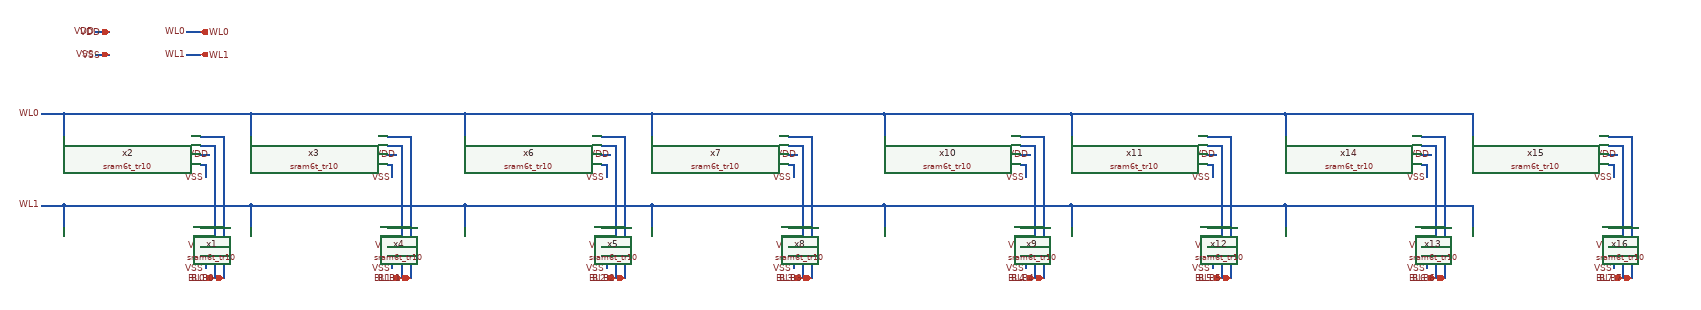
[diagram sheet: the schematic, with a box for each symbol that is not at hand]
v {xschem version=3.4.8RC file_version=1.3}
G {}
K {}
V {}
S {}
F {}
E {}
N 50 -560 50 -510 {lab=WL0}
N 50 -560 460 -560 {lab=WL0}
N 460 -560 460 -510 {lab=WL0}
N 0 -560 50 -560 {lab=WL0}
N 50 -360 50 -310 {lab=WL1}
N 50 -360 460 -360 {lab=WL1}
N 460 -360 460 -310 {lab=WL1}
N -0 -360 50 -360 {lab=WL1}
N 350 -490 380 -490 {lab=BL0}
N 380 -490 380 -200 {lab=BL0}
N 350 -290 380 -290 {lab=BL0}
N 350 -510 400 -510 {lab=BLB0}
N 400 -510 400 -200 {lab=BLB0}
N 350 -310 400 -310 {lab=BLB0}
N 760 -490 790 -490 {lab=BL1}
N 790 -490 790 -200 {lab=BL1}
N 760 -290 790 -290 {lab=BL1}
N 760 -510 810 -510 {lab=BLB1}
N 810 -510 810 -200 {lab=BLB1}
N 760 -310 810 -310 {lab=BLB1}
N 350 -270 370 -270 {lab=VDD}
N 350 -470 370 -470 {lab=VDD}
N 350 -450 360 -450 {lab=VSS}
N 360 -450 360 -420 {lab=VSS}
N 350 -250 360 -250 {lab=VSS}
N 360 -250 360 -220 {lab=VSS}
N 760 -450 770 -450 {lab=VSS}
N 770 -450 770 -420 {lab=VSS}
N 760 -250 770 -250 {lab=VSS}
N 770 -250 770 -220 {lab=VSS}
N 760 -470 780 -470 {lab=VDD}
N 760 -270 780 -270 {lab=VDD}
N 120 -740 150 -740 {lab=VDD}
N 120 -690 150 -690 {lab=VSS}
N 320 -740 350 -740 {lab=WL0}
N 320 -690 350 -690 {lab=WL1}
N 930 -560 930 -510 {lab=WL0}
N 930 -560 1340 -560 {lab=WL0}
N 1340 -560 1340 -510 {lab=WL0}
N 880 -560 930 -560 {lab=WL0}
N 930 -360 930 -310 {lab=WL1}
N 930 -360 1340 -360 {lab=WL1}
N 1340 -360 1340 -310 {lab=WL1}
N 880 -360 930 -360 {lab=WL1}
N 1230 -490 1260 -490 {lab=BL2}
N 1260 -490 1260 -200 {lab=BL2}
N 1230 -290 1260 -290 {lab=BL2}
N 1230 -510 1280 -510 {lab=BLB2}
N 1280 -510 1280 -200 {lab=BLB2}
N 1230 -310 1280 -310 {lab=BLB2}
N 1640 -490 1670 -490 {lab=BL3}
N 1670 -490 1670 -200 {lab=BL3}
N 1640 -290 1670 -290 {lab=BL3}
N 1640 -510 1690 -510 {lab=BLB3}
N 1690 -510 1690 -200 {lab=BLB3}
N 1640 -310 1690 -310 {lab=BLB3}
N 1230 -270 1250 -270 {lab=VDD}
N 1230 -470 1250 -470 {lab=VDD}
N 1230 -450 1240 -450 {lab=VSS}
N 1240 -450 1240 -420 {lab=VSS}
N 1230 -250 1240 -250 {lab=VSS}
N 1240 -250 1240 -220 {lab=VSS}
N 1640 -450 1650 -450 {lab=VSS}
N 1650 -450 1650 -420 {lab=VSS}
N 1640 -250 1650 -250 {lab=VSS}
N 1650 -250 1650 -220 {lab=VSS}
N 1640 -470 1660 -470 {lab=VDD}
N 1640 -270 1660 -270 {lab=VDD}
N 460 -560 880 -560 {lab=WL0}
N 460 -360 880 -360 {lab=WL1}
N 1850 -560 1850 -510 {lab=WL0}
N 1850 -560 2260 -560 {lab=WL0}
N 2260 -560 2260 -510 {lab=WL0}
N 1800 -560 1850 -560 {lab=WL0}
N 1850 -360 1850 -310 {lab=WL1}
N 1850 -360 2260 -360 {lab=WL1}
N 2260 -360 2260 -310 {lab=WL1}
N 1800 -360 1850 -360 {lab=WL1}
N 2150 -490 2180 -490 {lab=BL4}
N 2180 -490 2180 -200 {lab=BL4}
N 2150 -290 2180 -290 {lab=BL4}
N 2150 -510 2200 -510 {lab=BLB4}
N 2200 -510 2200 -200 {lab=BLB4}
N 2150 -310 2200 -310 {lab=BLB4}
N 2560 -490 2590 -490 {lab=BL5}
N 2590 -490 2590 -200 {lab=BL5}
N 2560 -290 2590 -290 {lab=BL5}
N 2560 -510 2610 -510 {lab=BLB5}
N 2610 -510 2610 -200 {lab=BLB5}
N 2560 -310 2610 -310 {lab=BLB5}
N 2150 -270 2170 -270 {lab=VDD}
N 2150 -470 2170 -470 {lab=VDD}
N 2150 -450 2160 -450 {lab=VSS}
N 2160 -450 2160 -420 {lab=VSS}
N 2150 -250 2160 -250 {lab=VSS}
N 2160 -250 2160 -220 {lab=VSS}
N 2560 -450 2570 -450 {lab=VSS}
N 2570 -450 2570 -420 {lab=VSS}
N 2560 -250 2570 -250 {lab=VSS}
N 2570 -250 2570 -220 {lab=VSS}
N 2560 -470 2580 -470 {lab=VDD}
N 2560 -270 2580 -270 {lab=VDD}
N 2730 -560 2730 -510 {lab=WL0}
N 2730 -560 3140 -560 {lab=WL0}
N 3140 -560 3140 -510 {lab=WL0}
N 2680 -560 2730 -560 {lab=WL0}
N 2730 -360 2730 -310 {lab=WL1}
N 2730 -360 3140 -360 {lab=WL1}
N 3140 -360 3140 -310 {lab=WL1}
N 2680 -360 2730 -360 {lab=WL1}
N 3030 -490 3060 -490 {lab=BL6}
N 3060 -490 3060 -200 {lab=BL6}
N 3030 -290 3060 -290 {lab=BL6}
N 3030 -510 3080 -510 {lab=BLB6}
N 3080 -510 3080 -200 {lab=BLB6}
N 3030 -310 3080 -310 {lab=BLB6}
N 3440 -490 3470 -490 {lab=BL7}
N 3470 -490 3470 -200 {lab=BL7}
N 3440 -290 3470 -290 {lab=BL7}
N 3440 -510 3490 -510 {lab=BLB6}
N 3490 -510 3490 -200 {lab=BLB6}
N 3440 -310 3490 -310 {lab=BLB6}
N 3030 -270 3050 -270 {lab=VDD}
N 3030 -470 3050 -470 {lab=VDD}
N 3030 -450 3040 -450 {lab=VSS}
N 3040 -450 3040 -420 {lab=VSS}
N 3030 -250 3040 -250 {lab=VSS}
N 3040 -250 3040 -220 {lab=VSS}
N 3440 -450 3450 -450 {lab=VSS}
N 3450 -450 3450 -420 {lab=VSS}
N 3440 -250 3450 -250 {lab=VSS}
N 3450 -250 3450 -220 {lab=VSS}
N 3440 -470 3460 -470 {lab=VDD}
N 3440 -270 3460 -270 {lab=VDD}
N 2260 -560 2680 -560 {lab=WL0}
N 2260 -360 2680 -360 {lab=WL1}
N 1340 -560 1800 -560 {lab=WL0}
N 1340 -360 1800 -360 {lab=WL1}
C {devices/lab_pin.sym} 370 -470 1 1 {name=p1 sig_type=std_logic lab=VDD}
C {devices/lab_pin.sym} 780 -470 1 1 {name=p2 sig_type=std_logic lab=VDD}
C {devices/lab_pin.sym} 370 -270 1 1 {name=p3 sig_type=std_logic lab=VDD}
C {devices/lab_pin.sym} 780 -270 1 1 {name=p4 sig_type=std_logic lab=VDD}
C {devices/lab_pin.sym} 0 -560 0 0 {name=p5 sig_type=std_logic lab=WL0}
C {devices/lab_pin.sym} 0 -360 0 0 {name=p6 sig_type=std_logic lab=WL1}
C {devices/lab_pin.sym} 360 -420 1 1 {name=p11 sig_type=std_logic lab=VSS}
C {devices/lab_pin.sym} 770 -420 1 1 {name=p12 sig_type=std_logic lab=VSS}
C {devices/lab_pin.sym} 360 -220 1 1 {name=p13 sig_type=std_logic lab=VSS}
C {devices/lab_pin.sym} 770 -220 1 1 {name=p14 sig_type=std_logic lab=VSS}
C {devices/iopin.sym} 150 -740 0 0 {name=p15 lab=VDD}
C {devices/iopin.sym} 150 -690 0 0 {name=p16 lab=VSS}
C {devices/lab_pin.sym} 120 -740 0 0 {name=p23 sig_type=std_logic lab=VDD}
C {devices/lab_pin.sym} 120 -690 0 0 {name=p24 sig_type=std_logic lab=VSS}
C {devices/lab_pin.sym} 320 -740 0 0 {name=p25 sig_type=std_logic lab=WL0}
C {devices/lab_pin.sym} 320 -690 0 0 {name=p26 sig_type=std_logic lab=WL1}
C {devices/ipin.sym} 350 -740 0 1 {name=p17 lab=WL0}
C {devices/ipin.sym} 350 -690 0 1 {name=p18 lab=WL1}
C {sram6t_tr10.sym} 200 -280 0 0 {name=x1}
C {sram6t_tr10.sym} 200 -480 0 0 {name=x2}
C {sram6t_tr10.sym} 610 -480 0 0 {name=x3}
C {sram6t_tr10.sym} 610 -280 0 0 {name=x4}
C {devices/lab_pin.sym} 1250 -470 1 1 {name=p31 sig_type=std_logic lab=VDD}
C {devices/lab_pin.sym} 1660 -470 1 1 {name=p32 sig_type=std_logic lab=VDD}
C {devices/lab_pin.sym} 1250 -270 1 1 {name=p33 sig_type=std_logic lab=VDD}
C {devices/lab_pin.sym} 1660 -270 1 1 {name=p34 sig_type=std_logic lab=VDD}
C {devices/lab_pin.sym} 1240 -420 1 1 {name=p39 sig_type=std_logic lab=VSS}
C {devices/lab_pin.sym} 1650 -420 1 1 {name=p40 sig_type=std_logic lab=VSS}
C {devices/lab_pin.sym} 1240 -220 1 1 {name=p41 sig_type=std_logic lab=VSS}
C {devices/lab_pin.sym} 1650 -220 1 1 {name=p42 sig_type=std_logic lab=VSS}
C {sram6t_tr10.sym} 1080 -280 0 0 {name=x5}
C {sram6t_tr10.sym} 1080 -480 0 0 {name=x6}
C {sram6t_tr10.sym} 1490 -480 0 0 {name=x7}
C {sram6t_tr10.sym} 1490 -280 0 0 {name=x8}
C {devices/lab_pin.sym} 2170 -470 1 1 {name=p43 sig_type=std_logic lab=VDD}
C {devices/lab_pin.sym} 2580 -470 1 1 {name=p44 sig_type=std_logic lab=VDD}
C {devices/lab_pin.sym} 2170 -270 1 1 {name=p45 sig_type=std_logic lab=VDD}
C {devices/lab_pin.sym} 2580 -270 1 1 {name=p46 sig_type=std_logic lab=VDD}
C {devices/lab_pin.sym} 2160 -420 1 1 {name=p51 sig_type=std_logic lab=VSS}
C {devices/lab_pin.sym} 2570 -420 1 1 {name=p52 sig_type=std_logic lab=VSS}
C {devices/lab_pin.sym} 2160 -220 1 1 {name=p53 sig_type=std_logic lab=VSS}
C {devices/lab_pin.sym} 2570 -220 1 1 {name=p54 sig_type=std_logic lab=VSS}
C {sram6t_tr10.sym} 2000 -280 0 0 {name=x9}
C {sram6t_tr10.sym} 2000 -480 0 0 {name=x10}
C {sram6t_tr10.sym} 2410 -480 0 0 {name=x11}
C {sram6t_tr10.sym} 2410 -280 0 0 {name=x12}
C {devices/lab_pin.sym} 3050 -470 1 1 {name=p55 sig_type=std_logic lab=VDD}
C {devices/lab_pin.sym} 3460 -470 1 1 {name=p56 sig_type=std_logic lab=VDD}
C {devices/lab_pin.sym} 3050 -270 1 1 {name=p57 sig_type=std_logic lab=VDD}
C {devices/lab_pin.sym} 3460 -270 1 1 {name=p58 sig_type=std_logic lab=VDD}
C {devices/lab_pin.sym} 3040 -420 1 1 {name=p63 sig_type=std_logic lab=VSS}
C {devices/lab_pin.sym} 3450 -420 1 1 {name=p64 sig_type=std_logic lab=VSS}
C {devices/lab_pin.sym} 3040 -220 1 1 {name=p65 sig_type=std_logic lab=VSS}
C {devices/lab_pin.sym} 3450 -220 1 1 {name=p66 sig_type=std_logic lab=VSS}
C {sram6t_tr10.sym} 2880 -280 0 0 {name=x13}
C {sram6t_tr10.sym} 2880 -480 0 0 {name=x14}
C {sram6t_tr10.sym} 3290 -480 0 0 {name=x15}
C {sram6t_tr10.sym} 3290 -280 0 0 {name=x16}
C {devices/iopin.sym} 380 -200 1 0 {name=p91 lab=BL0}
C {devices/iopin.sym} 400 -200 1 0 {name=p92 lab=BLB0}
C {devices/iopin.sym} 790 -200 1 0 {name=p7 lab=BL1}
C {devices/iopin.sym} 810 -200 1 0 {name=p8 lab=BLB1}
C {devices/iopin.sym} 1260 -200 1 0 {name=p9 lab=BL2}
C {devices/iopin.sym} 1280 -200 1 0 {name=p10 lab=BLB2}
C {devices/iopin.sym} 1670 -200 1 0 {name=p19 lab=BL3}
C {devices/iopin.sym} 1690 -200 1 0 {name=p20 lab=BLB3}
C {devices/iopin.sym} 2180 -200 1 0 {name=p21 lab=BL4}
C {devices/iopin.sym} 2200 -200 1 0 {name=p22 lab=BLB4}
C {devices/iopin.sym} 2590 -200 1 0 {name=p27 lab=BL5}
C {devices/iopin.sym} 2610 -200 1 0 {name=p28 lab=BLB5}
C {devices/iopin.sym} 3060 -200 1 0 {name=p29 lab=BL6}
C {devices/iopin.sym} 3080 -200 1 0 {name=p30 lab=BLB6}
C {devices/iopin.sym} 3470 -200 1 0 {name=p35 lab=BL7}
C {devices/iopin.sym} 3490 -200 1 0 {name=p36 lab=BLB7}
